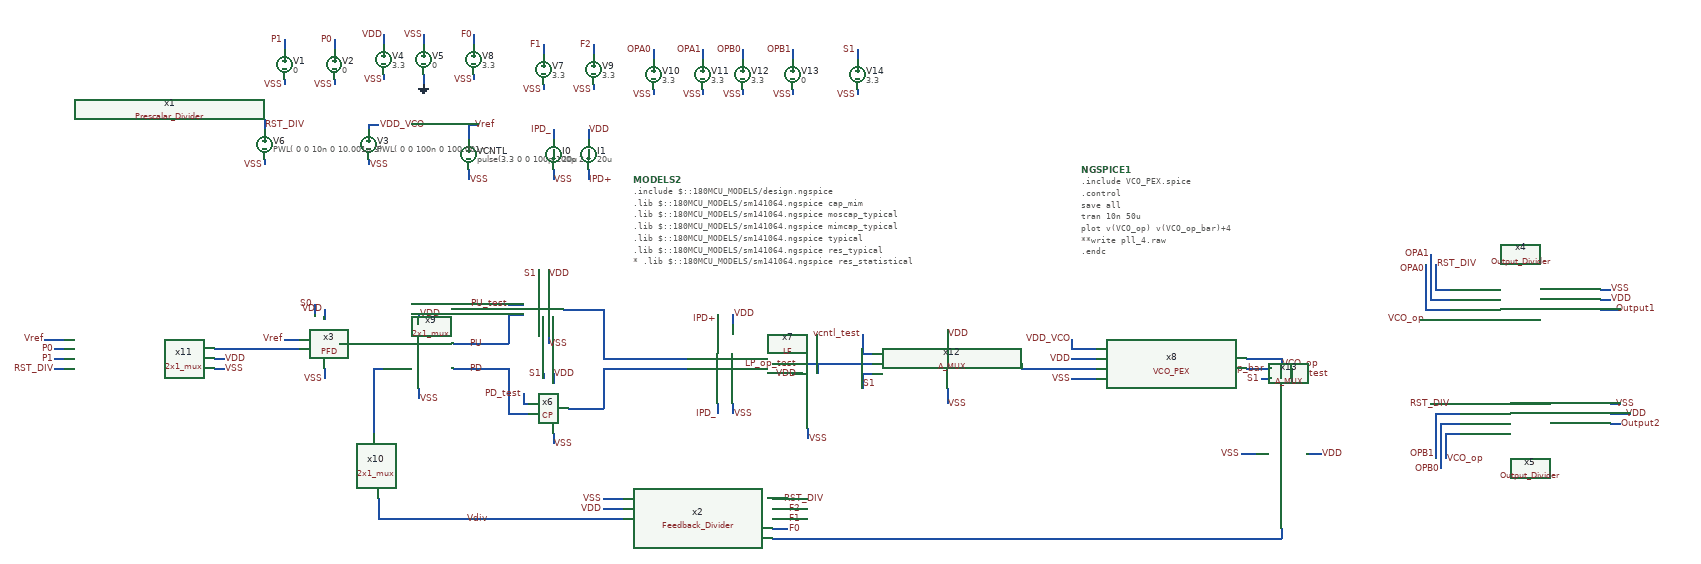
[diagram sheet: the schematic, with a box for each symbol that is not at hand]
v {xschem version=3.1.0 file_version=1.2
}
G {}
K {}
V {}
S {}
E {}
N 20 -560 40 -560 {
lab=P0}
N 20 -540 40 -540 {
lab=P1}
N 20 -520 40 -520 {
lab=RST_DIV}
N 340 -520 360 -520 {
lab=VSS}
N 340 -540 360 -540 {
lab=VDD}
N 480 -1100 480 -1090 {
lab=VSS}
N 480 -1180 480 -1160 {
lab=P1}
N 580 -1100 580 -1090 {
lab=VSS}
N 580 -1180 580 -1160 {
lab=P0}
N 750 -630 750 -610 {
lab=VDD}
N 750 -480 750 -460 {
lab=VSS}
N 660 -570 680 -570 {
lab=#net1}
N 660 -520 680 -520 {
lab=#net2}
N 820 -520 840 -520 {
lab=PD}
N 640 -570 660 -570 {
lab=#net1}
N 840 -570 930 -570 {
lab=PU}
N 840 -520 930 -520 {
lab=PD}
N 1120 -540 1270 -540 {
lab=#net3}
N 1120 -520 1270 -520 {
lab=#net4}
N 660 -520 660 -390 {
lab=#net2}
N 870 -220 1160 -220 {
lab=Vdiv}
N 2060 -560 2100 -560 {
lab=VDD_VCO}
N 820 -570 840 -570 {
lab=PU}
N 850 -920 850 -900 {
lab=VSS}
N 650 -940 650 -930 {
lab=VSS}
N 850 -1010 870 -1010 {
lab=Vref}
N 680 -1110 680 -1100 {
lab=VSS}
N 680 -1190 680 -1170 {
lab=VDD}
N 760 -1190 760 -1170 {
lab=VSS}
N 760 -1110 760 -1090 {
lab=GND}
N 2060 -580 2060 -560 {
lab=VDD_VCO}
N 1120 -260 1160 -260 {
lab=VSS}
N 1120 -240 1160 -240 {
lab=VDD}
N 1460 -240 1490 -240 {
lab=F2}
N 1460 -260 1490 -260 {
lab=RST_DIV}
N 440 -940 440 -930 {
lab=VSS}
N 440 -1020 440 -1000 {
lab=RST_DIV}
N 1620 -530 1630 -530 {
lab=LP_op_test}
N 2100 -560 2110 -560 {
lab=VDD_VCO}
N 1460 -200 1490 -200 {
lab=F0}
N 1460 -220 1490 -220 {
lab=F1}
N 650 -1010 650 -1000 {
lab=VDD_VCO}
N 650 -1010 670 -1010 {
lab=VDD_VCO}
N 1000 -1090 1000 -1080 {
lab=VSS}
N 1000 -1170 1000 -1150 {
lab=F1}
N 860 -1110 860 -1100 {
lab=VSS}
N 860 -1190 860 -1170 {
lab=F0}
N 1100 -1090 1100 -1080 {
lab=VSS}
N 1100 -1170 1100 -1150 {
lab=F2}
N 2790 -680 2820 -680 {
lab=RST_DIV}
N 2790 -730 2790 -680 {
lab=RST_DIV}
N 2760 -620 2820 -620 {
lab=VCO_op}
N 2780 -660 2820 -660 {
lab=OPA1}
N 2780 -730 2780 -660 {
lab=OPA1}
N 2770 -640 2820 -640 {
lab=OPA0}
N 2770 -730 2770 -640 {
lab=OPA0}
N 3120 -680 3140 -680 {
lab=VSS}
N 3120 -660 3140 -660 {
lab=VDD}
N 3120 -640 3160 -640 {
lab=Output1}
N 2780 -750 2780 -730 {
lab=OPA1}
N 2810 -390 2840 -390 {
lab=VCO_op}
N 2810 -390 2810 -340 {
lab=VCO_op}
N 2780 -450 2840 -450 {
lab=RST_DIV}
N 2800 -410 2840 -410 {
lab=OPB0}
N 2800 -410 2800 -340 {
lab=OPB0}
N 2790 -430 2840 -430 {
lab=OPB1}
N 2790 -430 2790 -340 {
lab=OPB1}
N 3140 -450 3160 -450 {
lab=VSS}
N 3140 -410 3160 -410 {
lab=Output2}
N 3140 -430 3180 -430 {
lab=VDD}
N 2800 -340 2800 -320 {
lab=OPB0}
N 1220 -1080 1220 -1070 {
lab=VSS}
N 1220 -1160 1220 -1140 {
lab=OPA0}
N 1320 -1080 1320 -1070 {
lab=VSS}
N 1320 -1160 1320 -1140 {
lab=OPA1}
N 1400 -1080 1400 -1070 {
lab=VSS}
N 1400 -1160 1400 -1140 {
lab=OPB0}
N 1500 -1080 1500 -1070 {
lab=VSS}
N 1500 -1160 1500 -1140 {
lab=OPB1}
N 1380 -630 1380 -610 {
lab=VDD}
N 1380 -450 1380 -430 {
lab=VSS}
N 1270 -540 1290 -540 {
lab=#net3}
N 1270 -520 1290 -520 {
lab=#net4}
N 1530 -400 1530 -380 {
lab=VSS}
N 1350 -630 1350 -610 {
lab=IPD+}
N 1350 -450 1350 -430 {
lab=IPD_}
N 1460 -530 1620 -530 {
lab=LP_op_test}
N 1020 -920 1020 -900 {
lab=VSS}
N 1090 -920 1090 -900 {
lab=IPD+}
N 1020 -1000 1020 -980 {
lab=IPD_}
N 1090 -1000 1090 -980 {
lab=VDD}
N 430 -560 460 -560 {
lab=#net5}
N 1550 -530 1550 -510 {
lab=LP_op_test}
N 1500 -510 1520 -510 {
lab=VDD}
N 0 -580 30 -580 {
lab=Vref}
N 340 -560 410 -560 {
lab=#net5}
N 410 -560 430 -560 {
lab=#net5}
N 30 -580 40 -580 {
lab=Vref}
N 930 -520 930 -430 {
lab=PD}
N 930 -430 970 -430 {
lab=PD}
N 960 -450 970 -450 {
lab=PD_test}
N 960 -470 960 -450 {
lab=PD_test}
N 930 -630 930 -570 {
lab=PU}
N 930 -630 960 -630 {
lab=PU}
N 1010 -590 1010 -570 {
lab=VSS}
N 1000 -510 1000 -500 {
lab=S1}
N 1020 -510 1020 -490 {
lab=VDD}
N 1040 -640 1120 -640 {
lab=#net3}
N 1120 -640 1120 -570 {
lab=#net3}
N 1120 -520 1120 -440 {
lab=#net4}
N 1050 -440 1120 -440 {
lab=#net4}
N 1120 -570 1120 -540 {
lab=#net3}
N 990 -720 990 -700 {
lab=S1}
N 1010 -720 1010 -690 {
lab=VDD}
N 930 -650 960 -650 {
lab=PU_test}
N 1020 -390 1020 -370 {
lab=VSS}
N 560 -520 560 -500 {
lab=VSS}
N 560 -640 560 -620 {
lab=VDD}
N 540 -650 540 -630 {
lab=S0}
N 460 -560 510 -560 {
lab=#net5}
N 480 -580 510 -580 {
lab=Vdiv_test}
N 1630 -1080 1630 -1070 {
lab=VSS}
N 1630 -1160 1630 -1140 {
lab=S1}
N 1810 -600 1810 -580 {
lab=VDD}
N 1810 -480 1810 -450 {
lab=VSS}
N 1630 -530 1660 -530 {
lab=LP_op_test}
N 1640 -550 1660 -550 {
lab=vcntl_test}
N 1640 -590 1640 -550 {
lab=vcntl_test}
N 1640 -510 1660 -510 {
lab=S1}
N 1640 -510 1640 -480 {
lab=S1}
N 2500 -520 2500 -500 {
lab=Vo_test}
N 2480 -200 2480 -190 {
lab=#net6}
N 2400 -350 2430 -350 {
lab=VSS}
N 2530 -350 2560 -350 {
lab=VDD}
N 2440 -500 2460 -500 {
lab=S1}
N 2480 -190 2480 -180 {
lab=#net6}
N 2130 -180 2480 -180 {
lab=#net6}
N 670 -220 870 -220 {
lab=Vdiv}
N 670 -260 670 -220 {
lab=Vdiv}
N 1460 -180 2130 -180 {
lab=#net6}
N 850 -1010 850 -980 {
lab=Vref}
N 1960 -520 2110 -520 {
lab=#net7}
N 1960 -530 1960 -520 {
lab=#net7}
N 2060 -540 2110 -540 {
lab=VDD}
N 2060 -500 2110 -500 {
lab=VSS}
N 2410 -540 2480 -540 {
lab=VCO_op}
N 2410 -520 2460 -520 {
lab=VCO_op_bar}
N 2480 -540 2480 -500 {
lab=VCO_op}
N 590 -570 650 -570 {
lab=#net1}
C {devices/lab_pin.sym} 20 -540 0 0 {name=p139 sig_type=std_logic lab=P1}
C {devices/lab_pin.sym} 20 -560 0 0 {name=p140 sig_type=std_logic lab=P0}
C {devices/lab_pin.sym} 0 -580 0 0 {name=p141 sig_type=std_logic lab=Vref
}
C {devices/lab_pin.sym} 360 -520 2 0 {name=p142 sig_type=std_logic lab=VSS}
C {devices/lab_pin.sym} 360 -540 2 0 {name=p143 sig_type=std_logic lab=VDD}
C {devices/lab_pin.sym} 20 -520 0 0 {name=p144 sig_type=std_logic lab=RST_DIV}
C {devices/vsource.sym} 480 -1130 0 0 {name=V1 value=0}
C {devices/lab_wire.sym} 480 -1090 0 0 {name=p1 sig_type=std_logic lab=VSS
}
C {devices/lab_wire.sym} 480 -1180 0 0 {name=p2 sig_type=std_logic lab=P1}
C {devices/vsource.sym} 580 -1130 0 0 {name=V2 value=0}
C {devices/lab_wire.sym} 580 -1090 0 0 {name=p3 sig_type=std_logic lab=VSS
}
C {devices/lab_wire.sym} 580 -1180 0 0 {name=p4 sig_type=std_logic lab=P0}
C {PFD.sym} 460 -360 0 0 {name=x3}
C {devices/lab_pin.sym} 750 -630 2 0 {name=p9 sig_type=std_logic lab=VDD}
C {devices/lab_wire.sym} 750 -460 2 0 {name=p10 sig_type=std_logic lab=VSS}
C {devices/lab_pin.sym} 890 -220 1 0 {name=p28 sig_type=std_logic lab=Vdiv
}
C {devices/vsource.sym} 850 -950 0 0 {name=VCNTL value="pulse(3.3 0 0 100p 100p 250n 500n)"}
C {devices/vsource.sym} 650 -970 0 0 {name=V3 value=" PWL( 0 0 100n 0 100.001n 3.3)"}
C {devices/code_shown.sym} 2080 -920 0 1 {name=NGSPICE1 only_toplevel=true
value="
.include "VCO_PEX.spice"
.control
save all
tran 10n 50u 
plot v(VCO_op) v(VCO_op_bar)+4
**write pll_4.raw
.endc
"}
C {devices/vsource.sym} 680 -1140 0 0 {name=V4 value=3.3}
C {devices/vsource.sym} 760 -1140 0 0 {name=V5 value=0}
C {devices/lab_wire.sym} 760 -1190 0 0 {name=p7 sig_type=std_logic lab=VSS}
C {devices/lab_wire.sym} 680 -1100 0 0 {name=p8 sig_type=std_logic lab=VSS
}
C {devices/lab_wire.sym} 680 -1190 0 0 {name=p11 sig_type=std_logic lab=VDD}
C {devices/gnd.sym} 760 -1090 0 0 {name=l3 lab=GND}
C {devices/lab_pin.sym} 2060 -580 0 0 {name=p12 sig_type=std_logic lab=VDD_VCO}
C {devices/lab_pin.sym} 2450 -520 1 0 {name=p13 sig_type=std_logic lab=VCO_op_bar
}
C {devices/lab_pin.sym} 1120 -240 0 0 {name=p14 sig_type=std_logic lab=VDD}
C {devices/lab_wire.sym} 1120 -260 1 0 {name=p15 sig_type=std_logic lab=VSS}
C {devices/lab_pin.sym} 670 -1010 2 0 {name=p16 sig_type=std_logic lab=VDD_VCO}
C {devices/lab_pin.sym} 860 -1010 2 0 {name=p17 sig_type=std_logic lab=Vref
}
C {devices/lab_wire.sym} 440 -930 0 0 {name=p18 sig_type=std_logic lab=VSS
}
C {devices/vsource.sym} 440 -970 0 0 {name=V6 value=" PWL( 0 0 10n 0 10.001n 3)"}
C {devices/lab_pin.sym} 1510 -530 1 0 {name=p19 sig_type=std_logic lab=LP_op_test
}
C {devices/lab_pin.sym} 880 -570 1 0 {name=p20 sig_type=std_logic lab=PU}
C {devices/lab_pin.sym} 880 -520 1 0 {name=p21 sig_type=std_logic lab=PD}
C {Feedback_Divider.sym} 1310 -220 0 1 {name=x2}
C {devices/lab_pin.sym} 1490 -200 2 0 {name=p22 sig_type=std_logic lab=F0}
C {devices/lab_pin.sym} 1490 -220 2 0 {name=p23 sig_type=std_logic lab=F1}
C {devices/lab_pin.sym} 1490 -240 2 0 {name=p24 sig_type=std_logic lab=F2}
C {devices/vsource.sym} 1000 -1120 0 0 {name=V7 value=3.3}
C {devices/lab_wire.sym} 1000 -1080 0 0 {name=p26 sig_type=std_logic lab=VSS
}
C {devices/lab_wire.sym} 1000 -1170 0 0 {name=p27 sig_type=std_logic lab=F1}
C {devices/vsource.sym} 860 -1140 0 0 {name=V8 value=3.3}
C {devices/lab_wire.sym} 860 -1100 0 0 {name=p25 sig_type=std_logic lab=VSS
}
C {devices/lab_wire.sym} 860 -1190 0 0 {name=p29 sig_type=std_logic lab=F0}
C {devices/vsource.sym} 1100 -1120 0 0 {name=V9 value=3.3}
C {devices/lab_wire.sym} 1100 -1080 0 0 {name=p30 sig_type=std_logic lab=VSS
}
C {devices/lab_wire.sym} 1100 -1170 0 0 {name=p31 sig_type=std_logic lab=F2}
C {devices/lab_pin.sym} 3140 -660 2 0 {name=p32 sig_type=std_logic lab=VDD}
C {devices/lab_pin.sym} 3140 -680 2 0 {name=p33 sig_type=std_logic lab=VSS}
C {devices/lab_wire.sym} 2770 -720 0 0 {name=p82 sig_type=std_logic lab=OPA0}
C {devices/lab_wire.sym} 2780 -750 0 0 {name=p83 sig_type=std_logic lab=OPA1}
C {devices/lab_pin.sym} 2790 -730 2 0 {name=p34 sig_type=std_logic lab=RST_DIV}
C {devices/lab_pin.sym} 3150 -640 2 0 {name=p84 sig_type=std_logic lab=Output1}
C {devices/lab_pin.sym} 3170 -430 0 1 {name=p85 sig_type=std_logic lab=VDD}
C {devices/lab_pin.sym} 3150 -450 0 1 {name=p86 sig_type=std_logic lab=VSS}
C {devices/lab_wire.sym} 2790 -350 2 1 {name=p87 sig_type=std_logic lab=OPB1}
C {devices/lab_wire.sym} 2800 -320 2 1 {name=p88 sig_type=std_logic lab=OPB0}
C {devices/lab_pin.sym} 3160 -410 0 1 {name=p90 sig_type=std_logic lab=Output2}
C {Output_Divider.sym} 2990 -420 0 0 {name=x5}
C {devices/lab_pin.sym} 2820 -450 1 0 {name=p35 sig_type=std_logic lab=RST_DIV}
C {devices/lab_pin.sym} 2810 -340 2 0 {name=p37 sig_type=std_logic lab=VCO_op
}
C {devices/lab_pin.sym} 2770 -620 2 1 {name=p40 sig_type=std_logic lab=VCO_op
}
C {devices/vsource.sym} 1220 -1110 0 0 {name=V10 value=3.3}
C {devices/lab_wire.sym} 1220 -1070 0 0 {name=p41 sig_type=std_logic lab=VSS
}
C {devices/lab_wire.sym} 1220 -1160 0 0 {name=p42 sig_type=std_logic lab=OPA0}
C {devices/vsource.sym} 1320 -1110 0 0 {name=V11 value=3.3}
C {devices/lab_wire.sym} 1320 -1070 0 0 {name=p43 sig_type=std_logic lab=VSS
}
C {devices/lab_wire.sym} 1320 -1160 0 0 {name=p44 sig_type=std_logic lab=OPA1}
C {devices/vsource.sym} 1400 -1110 0 0 {name=V12 value=3.3}
C {devices/lab_wire.sym} 1400 -1070 0 0 {name=p45 sig_type=std_logic lab=VSS
}
C {devices/lab_wire.sym} 1400 -1160 0 0 {name=p46 sig_type=std_logic lab=OPB0
}
C {devices/vsource.sym} 1500 -1110 0 0 {name=V13 value=0}
C {devices/lab_wire.sym} 1500 -1070 0 0 {name=p47 sig_type=std_logic lab=VSS
}
C {devices/lab_wire.sym} 1500 -1160 0 0 {name=p48 sig_type=std_logic lab=OPB1}
C {devices/lab_pin.sym} 440 -1010 2 0 {name=p38 sig_type=std_logic lab=RST_DIV}
C {devices/lab_pin.sym} 1480 -260 2 0 {name=p39 sig_type=std_logic lab=RST_DIV}
C {devices/lab_wire.sym} 1380 -430 2 0 {name=p49 sig_type=std_logic lab=VSS}
C {devices/lab_pin.sym} 1380 -630 2 0 {name=p50 sig_type=std_logic lab=VDD}
C {CP.sym} 800 -330 0 0 {name=x6}
C {LF.sym} 1390 -350 0 0 {name=x7}
C {devices/lab_wire.sym} 1530 -380 2 0 {name=p51 sig_type=std_logic lab=VSS}
C {devices/lab_wire.sym} 1350 -620 0 0 {name=p52 sig_type=std_logic lab=IPD+}
C {devices/lab_wire.sym} 1350 -430 0 0 {name=p53 sig_type=std_logic lab=IPD_}
C {devices/isource.sym} 1020 -950 0 0 {name=I0 value=20u}
C {devices/isource.sym} 1090 -950 0 0 {name=I1 value=20u}
C {devices/lab_wire.sym} 1020 -1000 0 0 {name=p54 sig_type=std_logic lab=IPD_}
C {devices/lab_wire.sym} 1090 -900 2 0 {name=p55 sig_type=std_logic lab=IPD+}
C {devices/lab_wire.sym} 1020 -900 2 0 {name=p56 sig_type=std_logic lab=VSS}
C {devices/lab_wire.sym} 1090 -1000 2 0 {name=p57 sig_type=std_logic lab=VDD}
C {Output_Divider.sym} 2970 -650 0 0 {name=x4}
C {devices/code_shown.sym} 1180 -900 0 0 {name=MODELS2 only_toplevel=true
format="tcleval( @value )"
value="
.include $::180MCU_MODELS/design.ngspice
.lib $::180MCU_MODELS/sm141064.ngspice cap_mim
.lib $::180MCU_MODELS/sm141064.ngspice moscap_typical
.lib $::180MCU_MODELS/sm141064.ngspice mimcap_typical
.lib $::180MCU_MODELS/sm141064.ngspice typical
.lib $::180MCU_MODELS/sm141064.ngspice res_typical
* .lib $::180MCU_MODELS/sm141064.ngspice res_statistical
"}
C {devices/lab_pin.sym} 1510 -510 0 0 {name=p59 sig_type=std_logic lab=VDD}
C {Prescalar_Divider.sym} 190 -550 2 1 {name=x1}
C {devices/lab_wire.sym} 650 -930 2 0 {name=p5 sig_type=std_logic lab=VSS
}
C {devices/lab_wire.sym} 850 -900 2 0 {name=p6 sig_type=std_logic lab=VSS
}
C {devices/lab_pin.sym} 300 -560 0 0 {name=p58 sig_type=std_logic lab=Vref
}
C {2x1_mux.sym} 760 -520 0 0 {name=x9}
C {2x1_mux.sym} 770 -320 0 0 {name=x10}
C {devices/lab_pin.sym} 930 -650 0 0 {name=p60 sig_type=std_logic lab=PU_test
}
C {devices/lab_pin.sym} 960 -470 1 0 {name=p61 sig_type=std_logic lab=PD_test
}
C {devices/lab_pin.sym} 1010 -710 2 0 {name=p62 sig_type=std_logic lab=VDD}
C {devices/lab_pin.sym} 1020 -510 2 0 {name=p63 sig_type=std_logic lab=VDD}
C {devices/lab_wire.sym} 1020 -370 2 0 {name=p64 sig_type=std_logic lab=VSS}
C {devices/lab_wire.sym} 1010 -570 2 0 {name=p65 sig_type=std_logic lab=VSS}
C {devices/lab_pin.sym} 990 -710 1 0 {name=p106 sig_type=std_logic lab=S1}
C {devices/lab_pin.sym} 1000 -510 1 0 {name=p66 sig_type=std_logic lab=S1}
C {2x1_mux.sym} 310 -450 0 0 {name=x11}
C {devices/lab_wire.sym} 560 -500 3 0 {name=p67 sig_type=std_logic lab=VSS}
C {devices/lab_pin.sym} 560 -640 3 1 {name=p68 sig_type=std_logic lab=VDD}
C {devices/lab_pin.sym} 540 -650 1 0 {name=p69 sig_type=std_logic lab=S0}
C {devices/lab_pin.sym} 480 -580 1 0 {name=p70 sig_type=std_logic lab=Vref
}
C {devices/vsource.sym} 1630 -1110 0 0 {name=V14 value=3.3}
C {devices/lab_wire.sym} 1630 -1070 0 0 {name=p71 sig_type=std_logic lab=VSS
}
C {devices/lab_wire.sym} 1630 -1160 0 0 {name=p72 sig_type=std_logic lab=S1}
C {A_MUX.sym} 1810 -530 0 0 {name=x12}
C {devices/lab_pin.sym} 1810 -590 2 0 {name=p73 sig_type=std_logic lab=VDD}
C {devices/lab_wire.sym} 1810 -450 2 0 {name=p74 sig_type=std_logic lab=VSS}
C {devices/lab_pin.sym} 1640 -490 2 0 {name=p75 sig_type=std_logic lab=S1}
C {devices/lab_pin.sym} 1640 -590 0 0 {name=p76 sig_type=std_logic lab=vcntl_test
}
C {devices/lab_pin.sym} 2480 -530 2 0 {name=p77 sig_type=std_logic lab=VCO_op
}
C {devices/lab_pin.sym} 2500 -510 2 0 {name=p78 sig_type=std_logic lab=Vo_test
}
C {A_MUX.sym} 2480 -350 1 0 {name=x13}
C {devices/lab_pin.sym} 2440 -500 0 0 {name=p79 sig_type=std_logic lab=S1}
C {devices/lab_wire.sym} 2400 -350 0 0 {name=p36 sig_type=std_logic lab=VSS}
C {devices/lab_pin.sym} 2560 -350 2 0 {name=p80 sig_type=std_logic lab=VDD}
C {VCO_PEX.sym} 2260 -530 0 0 {name=x8}
C {devices/lab_pin.sym} 2060 -540 0 0 {name=p81 sig_type=std_logic lab=VDD}
C {devices/lab_wire.sym} 2060 -500 2 1 {name=p89 sig_type=std_logic lab=VSS}
